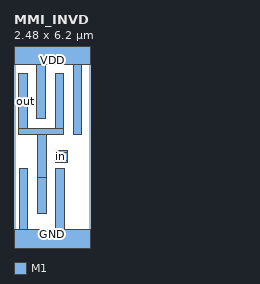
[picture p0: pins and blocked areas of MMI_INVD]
MACRO MMI_INVD
	CLASS CORE ;
	FOREIGN MMI_INVD 0 0 ;
	SIZE 2.48 BY 6.2 ;
	SYMMETRY X Y ;
	SITE CORE1 ;
	PIN out
		DIRECTION output ;
		USE SIGNAL ;
		PORT
			LAYER M1 ;
			RECT 0.16 3.69 0.44 5.485 ;
			LAYER M1 ;
			RECT 1.34 3.69 1.62 5.485 ;
			LAYER M1 ;
			RECT 0.16 3.5 1.62 3.69 ;
			LAYER M1 ;
			RECT 0.76 2.115 1.045 3.5 ;
			LAYER M1 ;
			RECT 0.765 0.925 1.045 2.115 ;
		END
		AntennaDiffArea 2.393525 ;
	END out
	PIN GND
		DIRECTION inout ;
		USE GROUND ;
		PORT
			LAYER M1 ;
			RECT 0.175 0.42 0.455 2.395 ;
			LAYER M1 ;
			RECT 1.355 0.42 1.635 2.395 ;
			LAYER M1 ;
			RECT 0 -0.42 2.48 0.42 ;
		END
	END GND
	PIN VDD
		DIRECTION inout ;
		USE POWER ;
		PORT
			LAYER M1 ;
			RECT 0 5.78 2.48 6.62 ;
			LAYER M1 ;
			RECT 0.75 4.03 1.03 5.78 ;
			LAYER M1 ;
			RECT 1.93 3.5 2.21 5.78 ;
		END
	END VDD
	PIN in
		DIRECTION input ;
		USE SIGNAL ;
		PORT
			LAYER M1 ;
			RECT 1.36 2.93 1.74 2.98 ;
			LAYER M1 ;
			RECT 1.31 2.65 1.74 2.93 ;
			LAYER M1 ;
			RECT 1.36 2.6 1.74 2.65 ;
		END
		AntennaGateArea 1.38675 ;
	END in
	OBS
	END
END MMI_INVD
